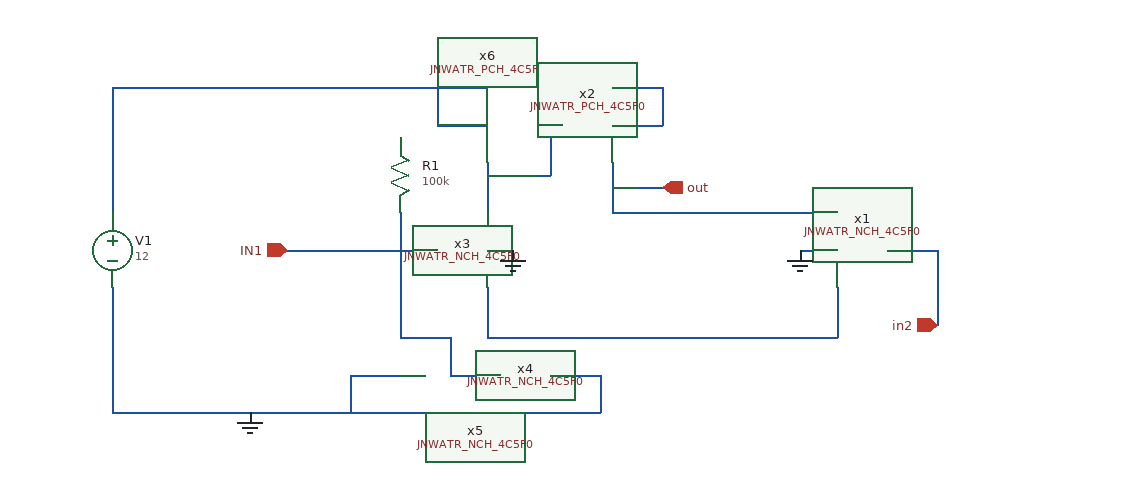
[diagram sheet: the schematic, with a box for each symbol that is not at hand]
v {xschem version=3.4.6 file_version=1.2}
G {}
K {}
V {}
S {}
E {}
N -130 -70 -90 -70 {lab=#net1}
N 100 -110 100 -70 {lab=#net1}
N 90 -70 100 -70 {lab=#net1}
N -180 -110 -180 -70 {lab=#net1}
N -180 -70 -130 -70 {lab=#net1}
N -210 -40 -170 -40 {lab=#net2}
N -250 -70 -210 -70 {lab=#net2}
N -210 -70 -210 -40 {lab=#net2}
N -340 -140 -220 -140 {lab=IN1}
N -250 -170 -250 -70 {lab=#net2}
N -80 -210 -80 -170 {lab=out}
N 180 -140 180 -80 {lab=in2}
N 140 -140 180 -140 {lab=in2}
N -360 -10 -250 -10 {lab=GND}
N -250 -10 -130 -10 {lab=GND}
N -480 -110 -480 -10 {lab=GND}
N -480 -10 -360 -10 {lab=GND}
N -480 -270 -480 -170 {lab=#net3}
N -480 -270 -360 -270 {lab=#net3}
N -130 -40 -90 -40 {lab=GND}
N -90 -40 -90 -10 {lab=GND}
N -130 -10 -90 -10 {lab=GND}
N -290 -40 -250 -40 {lab=GND}
N -290 -40 -290 -10 {lab=GND}
N -80 -270 -40 -270 {lab=#net4}
N -40 -270 -40 -240 {lab=#net4}
N -180 -140 -160 -140 {lab=GND}
N 70 -140 100 -140 {lab=GND}
N -80 -170 0 -170 {lab=out}
N -90 -70 -10 -70 {lab=#net1}
N 0 -170 100 -170 {lab=out}
N -10 -70 90 -70 {lab=#net1}
N -80 -190 -40 -190 {lab=out}
N -140 -240 -120 -240 {lab=#net5}
N -130 -240 -130 -200 {lab=#net5}
N -180 -210 -180 -170 {lab=#net5}
N -180 -200 -130 -200 {lab=#net5}
N -80 -240 -40 -240 {lab=#net4}
N -220 -240 -180 -240 {lab=#net3}
N -230 -270 -180 -270 {lab=#net3}
N -220 -270 -220 -240 {lab=#net3}
N -360 -270 -230 -270 {lab=#net3}
C {/home/manu/pro/aicex/ip/jnw_atr_sky130a/design/JNW_ATR_SKY130A/JNWATR_NCH_4C5F0.sym} 140 -140 0 1 {name=x1 }
C {/home/manu/pro/aicex/ip/jnw_atr_sky130a/design/JNW_ATR_SKY130A/JNWATR_NCH_4C5F0.sym} -220 -140 0 0 {name=x3 }
C {/home/manu/pro/aicex/ip/jnw_atr_sky130a/design/JNW_ATR_SKY130A/JNWATR_NCH_4C5F0.sym} -170 -40 0 0 {name=x4 }
C {/home/manu/pro/aicex/ip/jnw_atr_sky130a/design/JNW_ATR_SKY130A/JNWATR_NCH_4C5F0.sym} -210 -40 0 1 {name=x5 }
C {opin.sym} -40 -190 0 0 {name=p3 lab=out
}
C {gnd.sym} -370 -10 0 0 {name=l4 lab=GND}
C {gnd.sym} 70 -140 0 0 {name=l1 lab=GND}
C {gnd.sym} -160 -140 0 0 {name=l2 lab=GND}
C {ipin.sym} -340 -140 0 0 {name=p1 lab=IN1}
C {ipin.sym} 180 -80 0 0 {name=p2 lab=in2}
C {vsource.sym} -480 -140 0 0 {name=V1 value=12 savecurrent=false}
C {res.sym} -250 -200 0 0 {name=R1
value=100k
footprint=1206
device=resistor
m=1}
C {/home/manu/pro/aicex/ip/jnw_gr01_sky130a/design/JNW_ATR_SKY130A/JNWATR_PCH_4C5F0.sym} -140 -240 0 1 {name=x6 }
C {/home/manu/pro/aicex/ip/jnw_gr01_sky130a/design/JNW_ATR_SKY130A/JNWATR_PCH_4C5F0.sym} -120 -240 0 0 {name=x2 }
